VERSION 5.8 ;
BUSBITCHARS "[]" ;
DIVIDERCHAR "/" ;
UNITS
  DATABASE MICRONS 1000 ;
END UNITS

LAYER ACTIVE
  TYPE MASTERSLICE ;
END ACTIVE

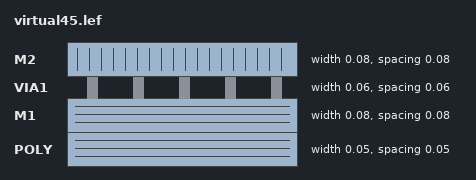
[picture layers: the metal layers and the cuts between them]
LAYER POLY
  TYPE ROUTING ;
  DIRECTION HORIZONTAL ;
  WIDTH 0.05 ;
  SPACING 0.05 ;
END POLY

LAYER M1
  TYPE ROUTING ;
  DIRECTION HORIZONTAL ;
  WIDTH 0.08 ;
  SPACING 0.08 ;
END M1

LAYER VIA1
  TYPE CUT ;
  WIDTH 0.06 ;
  SPACING 0.06 ;
END VIA1

LAYER M2
  TYPE ROUTING ;
  DIRECTION VERTICAL ;
  WIDTH 0.08 ;
  SPACING 0.08 ;
END M2

END LIBRARY
